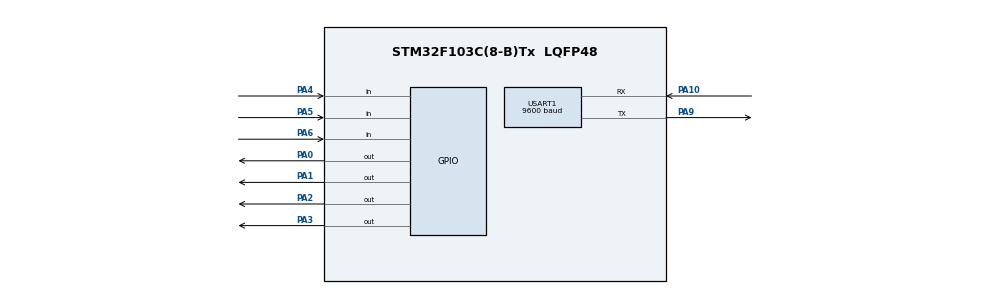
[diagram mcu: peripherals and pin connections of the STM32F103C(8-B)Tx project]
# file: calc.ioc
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Mcu.Family=STM32F1
RCC.PLLSourceVirtual=RCC_PLLSOURCE_HSE
PD1-OSC_OUT.Mode=HSE-External-Oscillator
PA10.Mode=Asynchronous
USART1.BaudRate=9600
PD0-OSC_IN.Signal=RCC_OSC_IN
RCC.APB1CLKDivider=RCC_HCLK_DIV2
VP_SYS_VS_ND.Mode=No_Debug
RCC.SYSCLKSource=RCC_SYSCLKSOURCE_PLLCLK
ProjectManager.StackSize=0x400
PA0-WKUP.Signal=GPIO_Output
PD1-OSC_OUT.Signal=RCC_OSC_OUT
PA9.Mode=Asynchronous
ProjectManager.TargetToolchain=STM32CubeIDE
RCC.HCLKFreq_Value=72000000
RCC.APB2TimFreq_Value=72000000
PA9.Signal=USART1_TX
RCC.USBFreq_Value=72000000
PA1.Signal=GPIO_Output
RCC.AHBFreq_Value=72000000
PD0-OSC_IN.Mode=HSE-External-Oscillator
PA5.Signal=GPIO_Input
board=custom
RCC.PLLMUL=RCC_PLL_MUL9
RCC.APB2Freq_Value=72000000
Mcu.Name=STM32F103C(8-B)Tx
PA2.Signal=GPIO_Output
PA4.Signal=GPIO_Input
RCC.SYSCLKFreq_VALUE=72000000
Mcu.Package=LQFP48
PA6.Signal=GPIO_Input
USART1.VirtualMode=VM_ASYNC
PA10.Signal=USART1_RX
ProjectManager.HeapSize=0x200
NVIC.PriorityGroup=NVIC_PRIORITYGROUP_4
RCC.APB1TimFreq_Value=72000000
RCC.APB1Freq_Value=36000000
PA3.Signal=GPIO_Output

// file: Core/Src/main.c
/* USER CODE BEGIN Header */
/**
  ******************************************************************************
  * @file           : main.c
  * @brief          : Main program body
  ******************************************************************************
  * @attention
  *
  * <h2><center>&copy; Copyright (c) 2024 STMicroelectronics.
  * All rights reserved.</center></h2>
  *
  * This software component is licensed by ST under BSD 3-Clause license,
  * the "License"; You may not use this file except in compliance with the
  * License. You may obtain a copy of the License at:
  *                        opensource.org/licenses/BSD-3-Clause
  *
  ******************************************************************************
  */
/* USER CODE END Header */
#include "main.h"
#include "arith_func.h"
#include "conversion.h"
#include "Error_handling.h"
#include "keypad.h"

UART_HandleTypeDef huart1;

void SystemClock_Config(void);
static void MX_GPIO_Init(void);
static void MX_USART1_UART_Init(void);

/* USER CODE BEGIN 0 */
void uart_string (char *str)
	{         //dispal string on screen
		int i;
		for(i=0;str[i]!=0;i++){   //send each character of the string till the null
			HAL_UART_Transmit(&huart1,&str[i], 1, 100);
			DELAY(4);
		}
	}
void clear()
{
	uint8_t clear='c';
	HAL_UART_Transmit(&huart1,&clear, 1, 100);
}

/* USER CODE END 0 */

int main(void)
{

  /* USER CODE BEGIN 1 */
		uint8_t operand1_hex[3]={0,0,0};
		uint8_t operand2_hex[3]={0,0,0};
		uint8_t opration_sign=0;
		uint8_t count,equal_sgin,Error_flag[4];
	    int operand1_dec,operand2_dec,result_dec,result_float=0;
	    uint8_t result_hex[3]={0,0,0};
	    uint8_t result_hex_float[3]={0,0,0};
	    uint8_t size,flag=0;
	    uint8_t da='o';

  /* USER CODE END 1 */

  /* MCU Configuration--------------------------------------------------------*/

  /* Reset of all peripherals, Initializes the Flash interface and the Systick. */
  HAL_Init();

  /* Configure the system clock */
  SystemClock_Config();

  /* Initialize all configured peripherals */
  MX_GPIO_Init();
  MX_USART1_UART_Init();

  /* Infinite loop */
  while (1)
  {
	  while(1)
	  {
	  for ( count = 0; count < 3; count++)
	     {
	     operand1_hex[count]=Keypad_GetVal();
	     if (operand1_hex[count]=='c')
	     {
	    	 flag=1;
	         break;

	     }
	     else
	     {
	    	 HAL_UART_Transmit(&huart1,&operand1_hex[count], 1, 100);
	    	 flag=0;
	     }
	     }

		if(flag!=0)
		{
		clear();
		break;
		}

	  opration_sign=Keypad_GetVal();
	  if(opration_sign=='c')
	  {
		  clear();
		  break;
	  }
	  else
	  {
		  HAL_UART_Transmit(&huart1,&opration_sign,1, 100);
	  }

	  for ( count = 0; count < 3; count++)
	  	     {
	  	     operand2_hex[count]=Keypad_GetVal();
	  	     if (operand2_hex[count]=='c')
	  	     {
	  	         flag=1;
	  	         break;

	  	     }
	  	     else
	  	     {
	  	    	 HAL_UART_Transmit(&huart1,&operand2_hex[count], 1, 100);
	  	    	 flag = 0;
	  	     }

	  	     }

		if(flag!=0)
		{
		clear();
		break;
		}

	    equal_sgin=Keypad_GetVal();
	    if (equal_sgin !='=')
	    {
	    	clear();
	       uart_string("Error\0");
	       break;
	    }
	    else
	    {
	    	HAL_UART_Transmit(&huart1,&equal_sgin, 1, 100);
	        DELAY(6);
	    }

	    Error_flag[0]=invldOpr(operand1_hex[0],operand1_hex[1],operand1_hex[2]);
	    Error_flag[1]=invldOpr(operand2_hex[0],operand2_hex[1],operand2_hex[2]);
	    Error_flag[2]=invldOpration(opration_sign);

	 	 if(Error_flag[0]==10 || Error_flag[1]==10 || Error_flag[2]==10 )
	 	    {
	 	        clear();
	 	        uart_string("INVALD\0");
	 	        break;
	 	    }

	    operand1_dec=hex_to_dec(operand1_hex[0],operand1_hex[1],operand1_hex[2]);
	    operand2_dec=hex_to_dec(operand2_hex[0],operand2_hex[1],operand2_hex[2]);
	    Error_flag[3]=divByZeroError(operand2_dec,opration_sign);

	            if(Error_flag[3]==10)
	        {
	            clear();
	            uart_string("INVALD\0");
	            break;
	        }
	            ArithFunc(operand1_dec,opration_sign,operand2_dec,&result_dec,&result_float);

	            if (operand1_dec<operand2_dec && opration_sign == '-')
	            {
	                uart_string("-\0");
	                result_dec = ~result_dec+1;
	            }
	            dec_to_hex_dec(result_dec, result_hex, &size);

	      	  for ( count = 0; count <=size; count++)
	      	  	     {
	      		HAL_UART_Transmit(&huart1, &result_hex[count], 1, 100);
	      			DELAY(5);
	      	  	     }
	      	  if(size==0)
	      	  {
	      		  	 uart_string("0\0");
	      	  }

			if(opration_sign=='/' && result_float!=0)
			{
			dec_to_hex(result_float,result_hex_float);
				uart_string(".\0");
				HAL_UART_Transmit(&huart1, &result_hex_float[0], 1, 100);
			if(result_hex_float[1] !='0' && result_hex_float[2] != '0')
			   HAL_UART_Transmit(&huart1, &result_hex_float[1], 1, 100);
			   if(result_hex_float[2]!='0')
				   HAL_UART_Transmit(&huart1, &result_hex_float[2], 1, 100);
			}

			Keypad_GetVal();
			clear();
	  }
	  Keypad_GetVal();
	  clear();

  }
}

void SystemClock_Config(void)
{
  RCC_OscInitTypeDef RCC_OscInitStruct = {0};
  RCC_ClkInitTypeDef RCC_ClkInitStruct = {0};

  /** Initializes the RCC Oscillators according to the specified parameters
  * in the RCC_OscInitTypeDef structure.
  */
  RCC_OscInitStruct.OscillatorType = RCC_OSCILLATORTYPE_HSI;
  RCC_OscInitStruct.HSIState = RCC_HSI_ON;
  RCC_OscInitStruct.HSICalibrationValue = RCC_HSICALIBRATION_DEFAULT;
  RCC_OscInitStruct.PLL.PLLState = RCC_PLL_NONE;
  if (HAL_RCC_OscConfig(&RCC_OscInitStruct) != HAL_OK)
  {
    Error_Handler();
  }
  /** Initializes the CPU, AHB and APB buses clocks
  */
  RCC_ClkInitStruct.ClockType = RCC_CLOCKTYPE_HCLK|RCC_CLOCKTYPE_SYSCLK
                              |RCC_CLOCKTYPE_PCLK1|RCC_CLOCKTYPE_PCLK2;
  RCC_ClkInitStruct.SYSCLKSource = RCC_SYSCLKSOURCE_HSI;
  RCC_ClkInitStruct.AHBCLKDivider = RCC_SYSCLK_DIV1;
  RCC_ClkInitStruct.APB1CLKDivider = RCC_HCLK_DIV1;
  RCC_ClkInitStruct.APB2CLKDivider = RCC_HCLK_DIV1;

  if (HAL_RCC_ClockConfig(&RCC_ClkInitStruct, FLASH_LATENCY_0) != HAL_OK)
  {
    Error_Handler();
  }
}

static void MX_USART1_UART_Init(void)
{

  huart1.Instance = USART1;
  huart1.Init.BaudRate = 9600;
  huart1.Init.WordLength = UART_WORDLENGTH_8B;
  huart1.Init.StopBits = UART_STOPBITS_1;
  huart1.Init.Parity = UART_PARITY_NONE;
  huart1.Init.Mode = UART_MODE_TX_RX;
  huart1.Init.HwFlowCtl = UART_HWCONTROL_NONE;
  huart1.Init.OverSampling = UART_OVERSAMPLING_16;
  if (HAL_UART_Init(&huart1) != HAL_OK)
  {
    Error_Handler();
  }

}

static void MX_GPIO_Init(void)
{
  GPIO_InitTypeDef GPIO_InitStruct = {0};

  /* GPIO Ports Clock Enable */
  __HAL_RCC_GPIOD_CLK_ENABLE();
  __HAL_RCC_GPIOA_CLK_ENABLE();

  /*Configure GPIO pin Output Level */
  HAL_GPIO_WritePin(GPIOA, GPIO_PIN_0|GPIO_PIN_1|GPIO_PIN_2|GPIO_PIN_3, GPIO_PIN_RESET);

  /*Configure GPIO pins : PA0 PA1 PA2 PA3 */
  GPIO_InitStruct.Pin = GPIO_PIN_0|GPIO_PIN_1|GPIO_PIN_2|GPIO_PIN_3;
  GPIO_InitStruct.Mode = GPIO_MODE_OUTPUT_PP;
  GPIO_InitStruct.Pull = GPIO_NOPULL;
  GPIO_InitStruct.Speed = GPIO_SPEED_FREQ_LOW;
  HAL_GPIO_Init(GPIOA, &GPIO_InitStruct);

  /*Configure GPIO pins : PA4 PA5 PA6 PA7 */
  GPIO_InitStruct.Pin = GPIO_PIN_4|GPIO_PIN_5|GPIO_PIN_6|GPIO_PIN_7;
  GPIO_InitStruct.Mode = GPIO_MODE_INPUT;
  GPIO_InitStruct.Pull = GPIO_NOPULL;
  HAL_GPIO_Init(GPIOA, &GPIO_InitStruct);

}

void Error_Handler(void)
{
  __disable_irq();
  while (1)
  {
  }
}

/************************ (C) COPYRIGHT STMicroelectronics *****END OF FILE****/
